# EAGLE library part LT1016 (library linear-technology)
Ultra-fast precision COMPARATOR

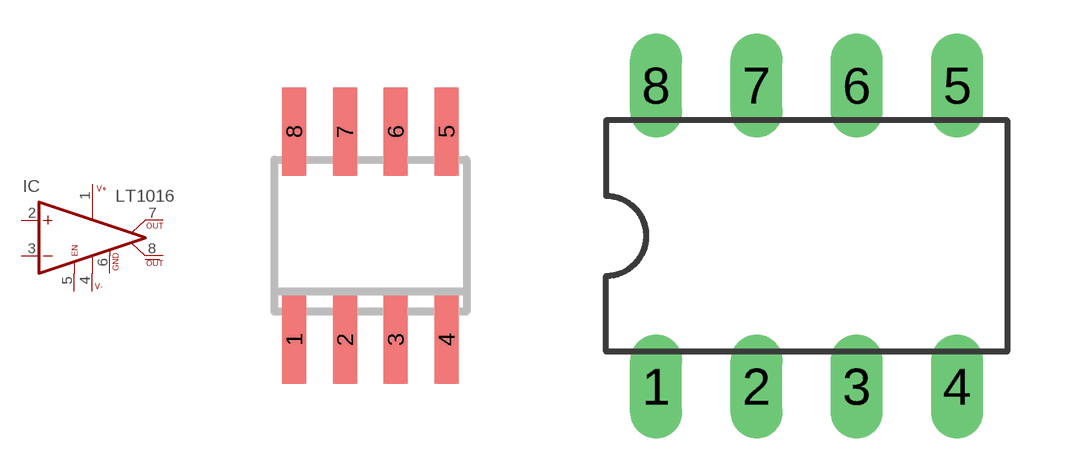
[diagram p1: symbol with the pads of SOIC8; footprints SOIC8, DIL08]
Designator prefix IC

## LT1016CS8 (MPN: LT1016CS8; OC_FARNELL: 796293; OC_NEWARK: 57M0854)  [SOIC8]
1  V+  pwr
2  +IN  in
3  -IN  in
4  V-  pwr
5  LA_EN  in
6  GND  pwr
7  OUT  out
8  !OUT  out

## LT1016CN (MPN: LT1016CN8; OC_FARNELL: 9559353; OC_NEWARK: 57M0852)  [DIL08]
Pads as for SOIC8

## Footprint SOIC8 (pad centres in mm)
Small Outline IC
smd 0.6 x 2.2: 1 -1.905,-2.6; 2 -0.635,-2.6; 3 0.635,-2.6; 4 1.905,-2.6; 5 1.905,2.6; 6 0.635,2.6; 7 -0.635,2.6; 8 -1.905,2.6

## Footprint DIL08 (pad centres in mm)
Dual In Line Package
drill 0.813 long: 1 -3.81,-3.81; 2 -1.27,-3.81; 3 1.27,-3.81; 4 3.81,-3.81; 5 3.81,3.81; 6 1.27,3.81; 7 -1.27,3.81; 8 -3.81,3.81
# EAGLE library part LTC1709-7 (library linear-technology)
Synchronous Step-Down Switching Regulator 2-Phase, 5-Bit VID, Current Mode, High Efficiency Source: www.linear.com/pc/downloadDocument.do?navId=H0,C1,C1003,C1042,C1143,C1083,P1964,D1133

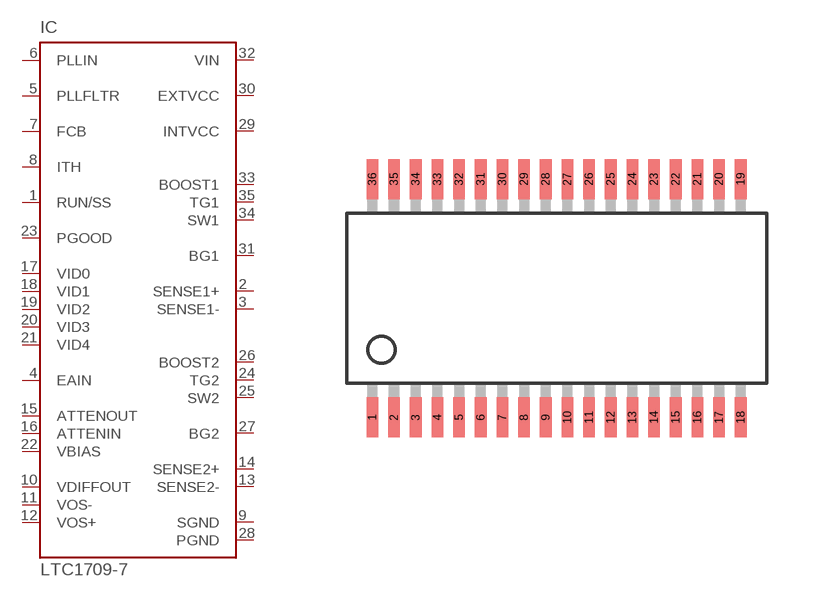
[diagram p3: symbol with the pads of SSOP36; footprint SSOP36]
Designator prefix IC

## LTC1709-7 (OC_FARNELL: unknown; OC_NEWARK: unknown)  [SSOP36]
1  RUN/SS  in
2  SENSE1+  in
3  SENSE1-  in
4  EAIN  in
5  PLLFLTR  pas
6  PLLIN  in
7  FCB  pas
8  ITH  out
9  SGND  pwr
10  VDIFFOUT  out
11  VOS-  in
12  VOS+  in
13  SENSE2-  in
14  SENSE2+  in
15  ATTENOUT  out
16  ATTENIN  in
17  VID0  in
18  VID1  in
19  VID2  in
20  VID3  in
21  VID4  in
22  VBIAS  pas
23  PGOOD  out
24  TG2  out
25  SW2  pas
26  BOOST2  pas
27  BG2  out
28  PGND  in
29  INTVCC  in
30  EXTVCC  in
31  BG1  out
32  VIN  in
33  BOOST1  pas
34  SW1  pas
35  TG1  out
36  NC  pas

## Footprint SSOP36 (pad centres in mm)
G Package 36-Lead Plastic SSOP (0.209) LTC DWG # 05-08-1640 Source: www.linear.com/pc/downloadDocument.do?navId=H0,C1,C1003,C1042,C1143,C1083,P1964,D1133
smd 0.35 x 1.2: 1 -5.525,-3.575; 2 -4.875,-3.575; 3 -4.225,-3.575; 4 -3.575,-3.575; 5 -2.925,-3.575; 6 -2.275,-3.575; 7 -1.625,-3.575; 8 -0.975,-3.575; 9 -0.325,-3.575; 10 0.325,-3.575; 11 0.975,-3.575; 12 1.625,-3.575; 13 2.275,-3.575; 14 2.925,-3.575; 15 3.575,-3.575; 16 4.225,-3.575; 17 4.875,-3.575; 18 5.525,-3.575; 19 5.525,3.575; 20 4.875,3.575; 21 4.225,3.575; 22 3.575,3.575; 23 2.925,3.575; 24 2.275,3.575; 25 1.625,3.575; 26 0.975,3.575; 27 0.325,3.575; 28 -0.325,3.575; 29 -0.975,3.575; 30 -1.625,3.575; 31 -2.275,3.575; 32 -2.925,3.575; 33 -3.575,3.575; 34 -4.225,3.575; 35 -4.875,3.575; 36 -5.525,3.575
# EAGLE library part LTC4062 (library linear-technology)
Standalone Linear Li-Ion Battery Charger with Micropower Comparator Source: http://www.linear.com .. 4062fa.pdf

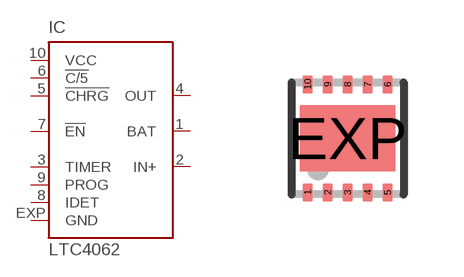
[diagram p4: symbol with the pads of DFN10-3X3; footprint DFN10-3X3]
Designator prefix IC

## LTC4062 (MPN: LTC4062EDD#PBF; OC_FARNELL: 1648037; OC_NEWARK: 58M0900)  [DFN10-3X3]
1  BAT  pas
2  IN+  in
3  TIMER  pas
4  OUT  oc
5  !CHRG  oc
6  !C/5  in
7  !EN  in
8  IDET  pas
9  PROG  pas
10  VCC  pwr
EXP  GND  pwr

## Footprint DFN10-3X3 (pad centres in mm)
DD Package 10-Lead Plastic DFN (3mm × 3mm) (Reference LTC DWG # 05-08-1669) Source: http://www.linear.com .. 4062fa.pdf
smd 0.25 x 0.45: 1 -1,-1.35; 2 -0.5,-1.35; 3 0,-1.35; 4 0.5,-1.35; 5 1,-1.35; 6 1,1.35; 7 0.5,1.35; 8 0,1.35; 9 -0.5,1.35; 10 -1,1.35
smd 2.38 x 1.65: EXP 0,0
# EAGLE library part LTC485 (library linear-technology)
Low Power RS485 Interface Transceiver Source: http://www.linear.com/pc/downloadDocument.do?navId=H0,C1,C1007,C1017,P2064,D1718

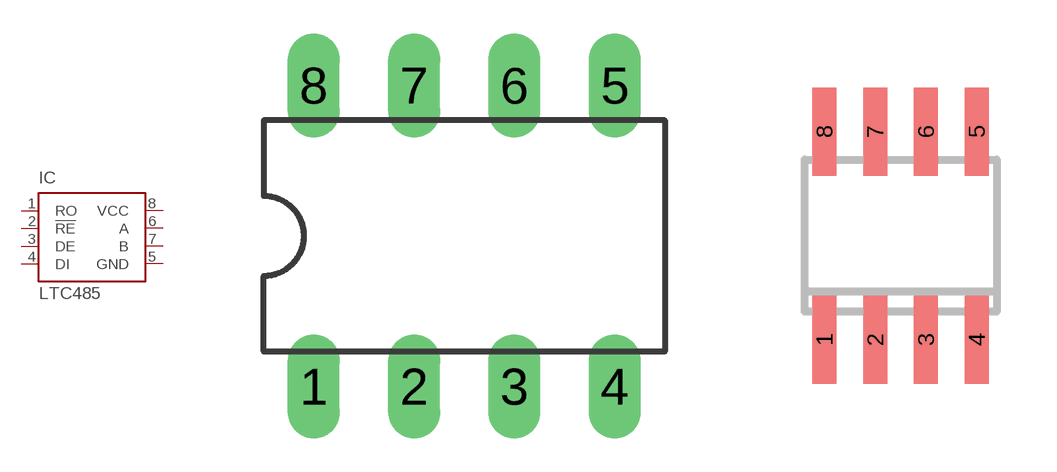
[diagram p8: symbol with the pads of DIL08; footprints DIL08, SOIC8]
Designator prefix IC

## LTC485N (OC_FARNELL: unknown; OC_NEWARK: unknown)  [DIL08]
1  RO  out
2  !RE  in
3  DE  in
4  DI  in
5  GND  in
6  A
7  B
8  VCC  in

## LTC485S (OC_FARNELL: unknown; OC_NEWARK: unknown)  [SOIC8]
Pads as for DIL08

## Footprint DIL08 (pad centres in mm)
Dual In Line Package
drill 0.813 long: 1 -3.81,-3.81; 2 -1.27,-3.81; 3 1.27,-3.81; 4 3.81,-3.81; 5 3.81,3.81; 6 1.27,3.81; 7 -1.27,3.81; 8 -3.81,3.81

## Footprint SOIC8 (pad centres in mm)
Small Outline IC
smd 0.6 x 2.2: 1 -1.905,-2.6; 2 -0.635,-2.6; 3 0.635,-2.6; 4 1.905,-2.6; 5 1.905,2.6; 6 0.635,2.6; 7 -0.635,2.6; 8 -1.905,2.6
